VERSION 5.7 ;
BUSBITCHARS "[]" ;
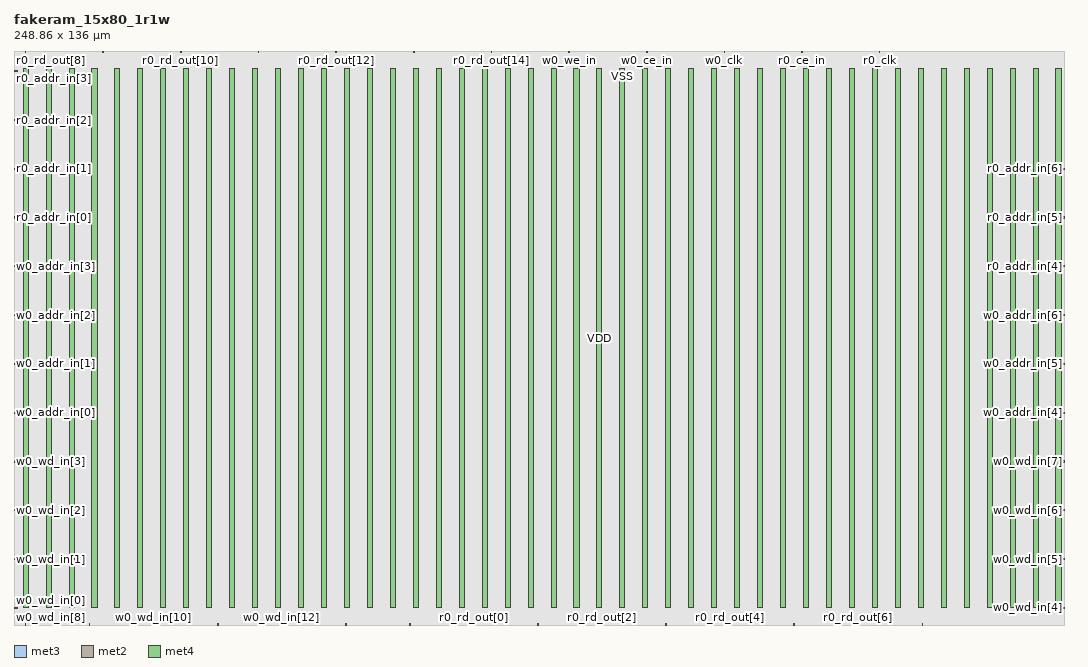
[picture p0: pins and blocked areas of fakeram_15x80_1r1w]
MACRO fakeram_15x80_1r1w
  FOREIGN fakeram_15x80_1r1w 0 0 ;
  SYMMETRY X Y R90 ;
  SIZE 248.860 BY 136.000 ;
  CLASS BLOCK ;
  PIN w0_wd_in[0]
    DIRECTION INPUT ;
    USE SIGNAL ;
    SHAPE ABUTMENT ;
    PORT
      LAYER met3 ;
      RECT 0.000 3.930 0.900 4.230 ;
    END
  END w0_wd_in[0]
  PIN w0_wd_in[1]
    DIRECTION INPUT ;
    USE SIGNAL ;
    SHAPE ABUTMENT ;
    PORT
      LAYER met3 ;
      RECT 0.000 15.490 0.900 15.790 ;
    END
  END w0_wd_in[1]
  PIN w0_wd_in[2]
    DIRECTION INPUT ;
    USE SIGNAL ;
    SHAPE ABUTMENT ;
    PORT
      LAYER met3 ;
      RECT 0.000 27.050 0.900 27.350 ;
    END
  END w0_wd_in[2]
  PIN w0_wd_in[3]
    DIRECTION INPUT ;
    USE SIGNAL ;
    SHAPE ABUTMENT ;
    PORT
      LAYER met3 ;
      RECT 0.000 38.610 0.900 38.910 ;
    END
  END w0_wd_in[3]
  PIN w0_wd_in[4]
    DIRECTION INPUT ;
    USE SIGNAL ;
    SHAPE ABUTMENT ;
    PORT
      LAYER met3 ;
      RECT 247.960 3.930 248.860 4.230 ;
    END
  END w0_wd_in[4]
  PIN w0_wd_in[5]
    DIRECTION INPUT ;
    USE SIGNAL ;
    SHAPE ABUTMENT ;
    PORT
      LAYER met3 ;
      RECT 247.960 15.490 248.860 15.790 ;
    END
  END w0_wd_in[5]
  PIN w0_wd_in[6]
    DIRECTION INPUT ;
    USE SIGNAL ;
    SHAPE ABUTMENT ;
    PORT
      LAYER met3 ;
      RECT 247.960 27.050 248.860 27.350 ;
    END
  END w0_wd_in[6]
  PIN w0_wd_in[7]
    DIRECTION INPUT ;
    USE SIGNAL ;
    SHAPE ABUTMENT ;
    PORT
      LAYER met3 ;
      RECT 247.960 38.610 248.860 38.910 ;
    END
  END w0_wd_in[7]
  PIN w0_wd_in[8]
    DIRECTION INPUT ;
    USE SIGNAL ;
    SHAPE ABUTMENT ;
    PORT
      LAYER met2 ;
      RECT 2.690 0.000 2.830 0.420 ;
    END
  END w0_wd_in[8]
  PIN w0_wd_in[9]
    DIRECTION INPUT ;
    USE SIGNAL ;
    SHAPE ABUTMENT ;
    PORT
      LAYER met2 ;
      RECT 17.870 0.000 18.010 0.420 ;
    END
  END w0_wd_in[9]
  PIN w0_wd_in[10]
    DIRECTION INPUT ;
    USE SIGNAL ;
    SHAPE ABUTMENT ;
    PORT
      LAYER met2 ;
      RECT 33.050 0.000 33.190 0.420 ;
    END
  END w0_wd_in[10]
  PIN w0_wd_in[11]
    DIRECTION INPUT ;
    USE SIGNAL ;
    SHAPE ABUTMENT ;
    PORT
      LAYER met2 ;
      RECT 48.230 0.000 48.370 0.420 ;
    END
  END w0_wd_in[11]
  PIN w0_wd_in[12]
    DIRECTION INPUT ;
    USE SIGNAL ;
    SHAPE ABUTMENT ;
    PORT
      LAYER met2 ;
      RECT 63.410 0.000 63.550 0.420 ;
    END
  END w0_wd_in[12]
  PIN w0_wd_in[13]
    DIRECTION INPUT ;
    USE SIGNAL ;
    SHAPE ABUTMENT ;
    PORT
      LAYER met2 ;
      RECT 78.590 0.000 78.730 0.420 ;
    END
  END w0_wd_in[13]
  PIN w0_wd_in[14]
    DIRECTION INPUT ;
    USE SIGNAL ;
    SHAPE ABUTMENT ;
    PORT
      LAYER met2 ;
      RECT 93.770 0.000 93.910 0.420 ;
    END
  END w0_wd_in[14]
  PIN r0_rd_out[0]
    DIRECTION OUTPUT ;
    USE SIGNAL ;
    SHAPE ABUTMENT ;
    PORT
      LAYER met2 ;
      RECT 108.950 0.000 109.090 0.420 ;
    END
  END r0_rd_out[0]
  PIN r0_rd_out[1]
    DIRECTION OUTPUT ;
    USE SIGNAL ;
    SHAPE ABUTMENT ;
    PORT
      LAYER met2 ;
      RECT 124.130 0.000 124.270 0.420 ;
    END
  END r0_rd_out[1]
  PIN r0_rd_out[2]
    DIRECTION OUTPUT ;
    USE SIGNAL ;
    SHAPE ABUTMENT ;
    PORT
      LAYER met2 ;
      RECT 139.310 0.000 139.450 0.420 ;
    END
  END r0_rd_out[2]
  PIN r0_rd_out[3]
    DIRECTION OUTPUT ;
    USE SIGNAL ;
    SHAPE ABUTMENT ;
    PORT
      LAYER met2 ;
      RECT 154.490 0.000 154.630 0.420 ;
    END
  END r0_rd_out[3]
  PIN r0_rd_out[4]
    DIRECTION OUTPUT ;
    USE SIGNAL ;
    SHAPE ABUTMENT ;
    PORT
      LAYER met2 ;
      RECT 169.670 0.000 169.810 0.420 ;
    END
  END r0_rd_out[4]
  PIN r0_rd_out[5]
    DIRECTION OUTPUT ;
    USE SIGNAL ;
    SHAPE ABUTMENT ;
    PORT
      LAYER met2 ;
      RECT 184.850 0.000 184.990 0.420 ;
    END
  END r0_rd_out[5]
  PIN r0_rd_out[6]
    DIRECTION OUTPUT ;
    USE SIGNAL ;
    SHAPE ABUTMENT ;
    PORT
      LAYER met2 ;
      RECT 200.030 0.000 200.170 0.420 ;
    END
  END r0_rd_out[6]
  PIN r0_rd_out[7]
    DIRECTION OUTPUT ;
    USE SIGNAL ;
    SHAPE ABUTMENT ;
    PORT
      LAYER met2 ;
      RECT 215.210 0.000 215.350 0.420 ;
    END
  END r0_rd_out[7]
  PIN r0_rd_out[8]
    DIRECTION OUTPUT ;
    USE SIGNAL ;
    SHAPE ABUTMENT ;
    PORT
      LAYER met2 ;
      RECT 2.690 135.580 2.830 136.000 ;
    END
  END r0_rd_out[8]
  PIN r0_rd_out[9]
    DIRECTION OUTPUT ;
    USE SIGNAL ;
    SHAPE ABUTMENT ;
    PORT
      LAYER met2 ;
      RECT 21.090 135.580 21.230 136.000 ;
    END
  END r0_rd_out[9]
  PIN r0_rd_out[10]
    DIRECTION OUTPUT ;
    USE SIGNAL ;
    SHAPE ABUTMENT ;
    PORT
      LAYER met2 ;
      RECT 39.490 135.580 39.630 136.000 ;
    END
  END r0_rd_out[10]
  PIN r0_rd_out[11]
    DIRECTION OUTPUT ;
    USE SIGNAL ;
    SHAPE ABUTMENT ;
    PORT
      LAYER met2 ;
      RECT 57.890 135.580 58.030 136.000 ;
    END
  END r0_rd_out[11]
  PIN r0_rd_out[12]
    DIRECTION OUTPUT ;
    USE SIGNAL ;
    SHAPE ABUTMENT ;
    PORT
      LAYER met2 ;
      RECT 76.290 135.580 76.430 136.000 ;
    END
  END r0_rd_out[12]
  PIN r0_rd_out[13]
    DIRECTION OUTPUT ;
    USE SIGNAL ;
    SHAPE ABUTMENT ;
    PORT
      LAYER met2 ;
      RECT 94.690 135.580 94.830 136.000 ;
    END
  END r0_rd_out[13]
  PIN r0_rd_out[14]
    DIRECTION OUTPUT ;
    USE SIGNAL ;
    SHAPE ABUTMENT ;
    PORT
      LAYER met2 ;
      RECT 113.090 135.580 113.230 136.000 ;
    END
  END r0_rd_out[14]
  PIN w0_addr_in[0]
    DIRECTION INPUT ;
    USE SIGNAL ;
    SHAPE ABUTMENT ;
    PORT
      LAYER met3 ;
      RECT 0.000 50.170 0.900 50.470 ;
    END
  END w0_addr_in[0]
  PIN w0_addr_in[1]
    DIRECTION INPUT ;
    USE SIGNAL ;
    SHAPE ABUTMENT ;
    PORT
      LAYER met3 ;
      RECT 0.000 61.730 0.900 62.030 ;
    END
  END w0_addr_in[1]
  PIN w0_addr_in[2]
    DIRECTION INPUT ;
    USE SIGNAL ;
    SHAPE ABUTMENT ;
    PORT
      LAYER met3 ;
      RECT 0.000 73.290 0.900 73.590 ;
    END
  END w0_addr_in[2]
  PIN w0_addr_in[3]
    DIRECTION INPUT ;
    USE SIGNAL ;
    SHAPE ABUTMENT ;
    PORT
      LAYER met3 ;
      RECT 0.000 84.850 0.900 85.150 ;
    END
  END w0_addr_in[3]
  PIN w0_addr_in[4]
    DIRECTION INPUT ;
    USE SIGNAL ;
    SHAPE ABUTMENT ;
    PORT
      LAYER met3 ;
      RECT 247.960 50.170 248.860 50.470 ;
    END
  END w0_addr_in[4]
  PIN w0_addr_in[5]
    DIRECTION INPUT ;
    USE SIGNAL ;
    SHAPE ABUTMENT ;
    PORT
      LAYER met3 ;
      RECT 247.960 61.730 248.860 62.030 ;
    END
  END w0_addr_in[5]
  PIN w0_addr_in[6]
    DIRECTION INPUT ;
    USE SIGNAL ;
    SHAPE ABUTMENT ;
    PORT
      LAYER met3 ;
      RECT 247.960 73.290 248.860 73.590 ;
    END
  END w0_addr_in[6]
  PIN r0_addr_in[0]
    DIRECTION INPUT ;
    USE SIGNAL ;
    SHAPE ABUTMENT ;
    PORT
      LAYER met3 ;
      RECT 0.000 96.410 0.900 96.710 ;
    END
  END r0_addr_in[0]
  PIN r0_addr_in[1]
    DIRECTION INPUT ;
    USE SIGNAL ;
    SHAPE ABUTMENT ;
    PORT
      LAYER met3 ;
      RECT 0.000 107.970 0.900 108.270 ;
    END
  END r0_addr_in[1]
  PIN r0_addr_in[2]
    DIRECTION INPUT ;
    USE SIGNAL ;
    SHAPE ABUTMENT ;
    PORT
      LAYER met3 ;
      RECT 0.000 119.530 0.900 119.830 ;
    END
  END r0_addr_in[2]
  PIN r0_addr_in[3]
    DIRECTION INPUT ;
    USE SIGNAL ;
    SHAPE ABUTMENT ;
    PORT
      LAYER met3 ;
      RECT 0.000 131.090 0.900 131.390 ;
    END
  END r0_addr_in[3]
  PIN r0_addr_in[4]
    DIRECTION INPUT ;
    USE SIGNAL ;
    SHAPE ABUTMENT ;
    PORT
      LAYER met3 ;
      RECT 247.960 84.850 248.860 85.150 ;
    END
  END r0_addr_in[4]
  PIN r0_addr_in[5]
    DIRECTION INPUT ;
    USE SIGNAL ;
    SHAPE ABUTMENT ;
    PORT
      LAYER met3 ;
      RECT 247.960 96.410 248.860 96.710 ;
    END
  END r0_addr_in[5]
  PIN r0_addr_in[6]
    DIRECTION INPUT ;
    USE SIGNAL ;
    SHAPE ABUTMENT ;
    PORT
      LAYER met3 ;
      RECT 247.960 107.970 248.860 108.270 ;
    END
  END r0_addr_in[6]
  PIN w0_we_in
    DIRECTION INPUT ;
    USE SIGNAL ;
    SHAPE ABUTMENT ;
    PORT
      LAYER met2 ;
      RECT 131.490 135.580 131.630 136.000 ;
    END
  END w0_we_in
  PIN w0_ce_in
    DIRECTION INPUT ;
    USE SIGNAL ;
    SHAPE ABUTMENT ;
    PORT
      LAYER met2 ;
      RECT 149.890 135.580 150.030 136.000 ;
    END
  END w0_ce_in
  PIN w0_clk
    DIRECTION INPUT ;
    USE SIGNAL ;
    SHAPE ABUTMENT ;
    PORT
      LAYER met2 ;
      RECT 168.290 135.580 168.430 136.000 ;
    END
  END w0_clk
  PIN r0_ce_in
    DIRECTION INPUT ;
    USE SIGNAL ;
    SHAPE ABUTMENT ;
    PORT
      LAYER met2 ;
      RECT 186.690 135.580 186.830 136.000 ;
    END
  END r0_ce_in
  PIN r0_clk
    DIRECTION INPUT ;
    USE SIGNAL ;
    SHAPE ABUTMENT ;
    PORT
      LAYER met2 ;
      RECT 205.090 135.580 205.230 136.000 ;
    END
  END r0_clk
  PIN VSS
    DIRECTION INOUT ;
    USE GROUND ;
    PORT
      LAYER met4 ;
      RECT 2.160 4.080 3.360 131.920 ;
      RECT 13.040 4.080 14.240 131.920 ;
      RECT 23.920 4.080 25.120 131.920 ;
      RECT 34.800 4.080 36.000 131.920 ;
      RECT 45.680 4.080 46.880 131.920 ;
      RECT 56.560 4.080 57.760 131.920 ;
      RECT 67.440 4.080 68.640 131.920 ;
      RECT 78.320 4.080 79.520 131.920 ;
      RECT 89.200 4.080 90.400 131.920 ;
      RECT 100.080 4.080 101.280 131.920 ;
      RECT 110.960 4.080 112.160 131.920 ;
      RECT 121.840 4.080 123.040 131.920 ;
      RECT 132.720 4.080 133.920 131.920 ;
      RECT 143.600 4.080 144.800 131.920 ;
      RECT 154.480 4.080 155.680 131.920 ;
      RECT 165.360 4.080 166.560 131.920 ;
      RECT 176.240 4.080 177.440 131.920 ;
      RECT 187.120 4.080 188.320 131.920 ;
      RECT 198.000 4.080 199.200 131.920 ;
      RECT 208.880 4.080 210.080 131.920 ;
      RECT 219.760 4.080 220.960 131.920 ;
      RECT 230.640 4.080 231.840 131.920 ;
      RECT 241.520 4.080 242.720 131.920 ;
    END
  END VSS
  PIN VDD
    DIRECTION INOUT ;
    USE POWER ;
    PORT
      LAYER met4 ;
      RECT 7.600 4.080 8.800 131.920 ;
      RECT 18.480 4.080 19.680 131.920 ;
      RECT 29.360 4.080 30.560 131.920 ;
      RECT 40.240 4.080 41.440 131.920 ;
      RECT 51.120 4.080 52.320 131.920 ;
      RECT 62.000 4.080 63.200 131.920 ;
      RECT 72.880 4.080 74.080 131.920 ;
      RECT 83.760 4.080 84.960 131.920 ;
      RECT 94.640 4.080 95.840 131.920 ;
      RECT 105.520 4.080 106.720 131.920 ;
      RECT 116.400 4.080 117.600 131.920 ;
      RECT 127.280 4.080 128.480 131.920 ;
      RECT 138.160 4.080 139.360 131.920 ;
      RECT 149.040 4.080 150.240 131.920 ;
      RECT 159.920 4.080 161.120 131.920 ;
      RECT 170.800 4.080 172.000 131.920 ;
      RECT 181.680 4.080 182.880 131.920 ;
      RECT 192.560 4.080 193.760 131.920 ;
      RECT 203.440 4.080 204.640 131.920 ;
      RECT 214.320 4.080 215.520 131.920 ;
      RECT 225.200 4.080 226.400 131.920 ;
      RECT 236.080 4.080 237.280 131.920 ;
      RECT 246.960 4.080 248.160 131.920 ;
    END
  END VDD
  OBS
    LAYER met1 ;
    RECT 0 0 248.860 136.000 ;
    LAYER met2 ;
    RECT 0 0 248.860 136.000 ;
    LAYER met3 ;
    RECT 0 0 248.860 136.000 ;
    LAYER met4 ;
    RECT 0 0 248.860 136.000 ;
  END
END fakeram_15x80_1r1w

END LIBRARY
